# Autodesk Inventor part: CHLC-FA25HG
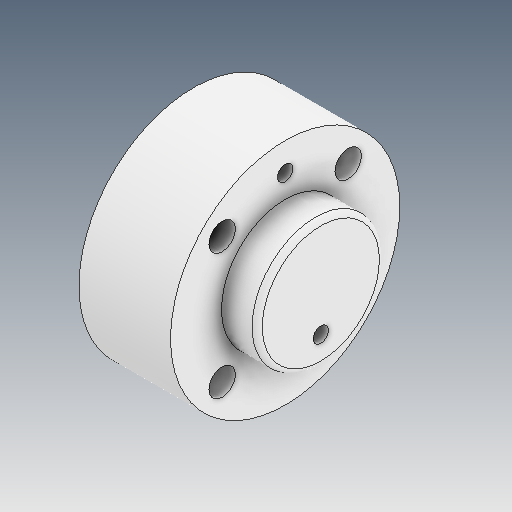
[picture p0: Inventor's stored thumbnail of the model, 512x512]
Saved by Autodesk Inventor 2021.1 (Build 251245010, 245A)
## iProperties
Created: 2021-05
Part Number: CHLC-FA25HG
Material: Ogólny
Document SubType Name: Modeling
Designer: user
Density: 1 g/cm^3
Appearance: Domyślna
Author: user
Revision Number: ÈÎºÎ
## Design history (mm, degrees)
feature "Ô²½Ç2"
node "Bryła1"
